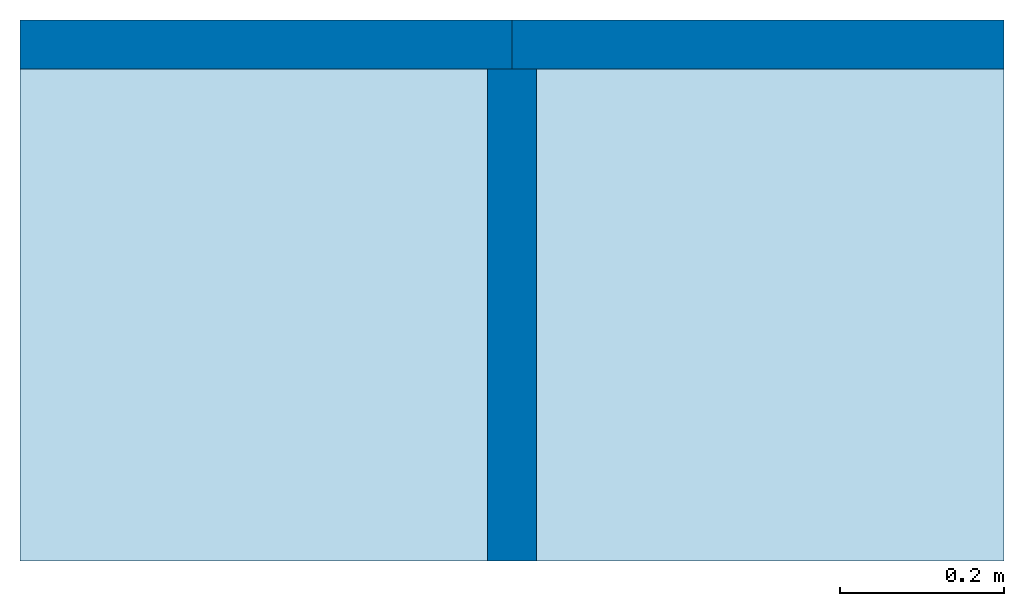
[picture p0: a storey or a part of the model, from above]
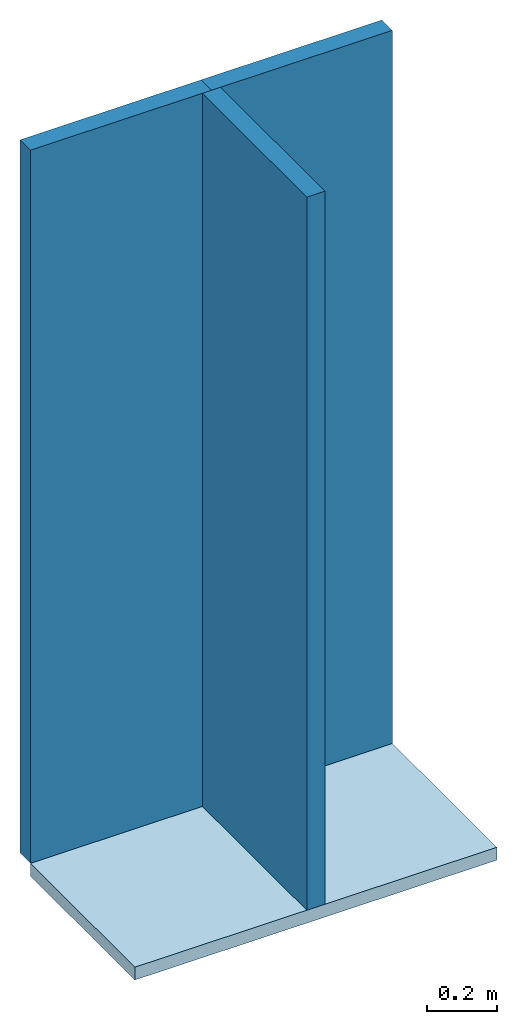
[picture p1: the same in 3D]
Properties of the parts of a building model (IFC2X3)

# File
Description: ViewDefinition [CoordinationView]
Time: 2023-01-18T13:22:00
Written by: The EXPRESS Data Manager Version 5.02.0100.07 : 28 Aug 2013
Made in: 21.1.70.21 - Exporter 21.1.70.21 - Alternate UI 21.1.70.21
Comment: STEP Physical File produced by: The EXPRESS Data Manager Version 5.02.0100.07 : 28 Aug 2013 * Module: EDMstepFileFactory/EDMstandAlone * Creation date: Wed Jan 18 13:22:00 2023 * Host: BIM-LT03 * Database: C:\Users\DONNEE~1\AppData\Local\Temp\6dfd9f73-01cb-4fe2-bb7c-203e315a706e\a5f62d73-1708-4fc1-9576-1699a38a04a9\ifc * Database version: 5507 * Database creation date: Wed Jan 18 13:22:00 2023 * Schema: IFC2X3 * Model: DataRepository.ifc * Model creation date: Wed Jan 18 13:22:00 2023 * Header model: DataRepository.ifc_HeaderModel * Header model creation date: Wed Jan 18 13:22:00 2023 * EDMuser: sdai-user * EDMgroup: sdai-group * License ID and type: 5605 : Permanent license. Expiry date: * EDMstepFileFactory options: 020000

# IfcSite, Default
RefLatitude: 42, 24, 53, 508911; RefLongitude: -71, -15, -29, -58837; RefElevation: 0 mm
Pset_ProductRequirements - Category: Project Information

# IfcBuilding
Pset_BuildingCommon - NumberOfStoreys: 1
Pset_ProductRequirements - Category: Project Information

# IfcBuildingStorey: Level:NL_00_niveau, Begane grond
LongName: Begane grond; Elevation: 0 mm
Pset_AirSideSystemInformation - Name: Begane grond
Pset_ProductRequirements - Name: Begane grond; Category: Levels

# IfcSlab: Floor:NLRS_23_FL_Ultracoustic_60x600x12000mm, Floor:NLRS_23_FL_Ultracoustic_60x600x12000mm:2487
In: Begane grond
Type - PredefinedType: FLOOR; Material: Knauf Insulation_Ecose® glaswol Ultracoustic 45 mm
Type - Pset_ElementShading - Roughness: 304.8 mm
Type - Pset_ManufacturerTypeInformation - Manufacturer: Knauf Insulation B.V.
Type - Pset_ProductRequirements - Category: Floors
Type - Pset_QuantityTakeOff - Reference: Floor:NLRS_23_FL_Ultracoustic_60x600x12000mm
Type - Pset_ReinforcementBarPitchOfSlab - Description: Ultracoustic - 60mm; Reference: Floor:NLRS_23_FL_Ultracoustic_60x600x12000mm
Type - Pset_SlabCommon - IsExternal: no; Reference: Floor:NLRS_23_FL_Ultracoustic_60x600x12000mm; ThermalTransmittance: 0.822222 kg/K/s3
Type - Pset_Floor Schedule Ultracoustic LOD200 - Assembly Code: 23; Type Image: Raster image: Ultracoustic.jpg (2); Model: Ultracoustic is een veerkrachtige onbeklede glaswoldeken met ECOSE® Technology; Manufacturer: Knauf Insulation B.V.; URL: www.knaufinsulation.nl; Description: Ultracoustic - 60mm
Classification: 23 Vloeren (Uniformat)
Pset_SlabCommon - LoadBearing: no; PitchAngle: 0 deg
Pset_Floor Schedule Ultracoustic LOD200 - Type: Floor: NLRS_23_FL_Ultracoustic_60x600x12000mm

# IfcWallStandardCase: Basic Wall:NLRS_22_WA_Ultracoustic_60x600x12000mm (3)
In: Begane grond
Type - PredefinedType: STANDARD; Material: Knauf Insulation_Ecose® glaswol Ultracoustic 60 mm
Type - Pset_ElementShading - Roughness: 304.8 mm
Type - Pset_ManufacturerTypeInformation - Manufacturer: Knauf Insulation B.V.
Type - Pset_ProductRequirements - Category: Walls
Type - Pset_QuantityTakeOff - Reference: Basic Wall:NLRS_22_WA_Ultracoustic_60x600x12000mm
Type - Pset_ReinforcementBarPitchOfWall - Description: Ultracoustic - 60mm; Reference: Basic Wall:NLRS_22_WA_Ultracoustic_60x600x12000mm
Type - Pset_WallCommon - Reference: Basic Wall:NLRS_22_WA_Ultracoustic_60x600x12000mm; ThermalTransmittance: 0.616667 kg/K/s3; IsExternal: no
Type - Pset_Wall Schedule Ultracoustic LOD200 - Assembly Code: 22; Type Image: Raster image: Ultracoustic.jpg (2); Model: Ultracoustic is een veerkrachtige onbeklede glaswoldeken met ECOSE® Technology; Manufacturer: Knauf Insulation B.V.; URL: www.knaufinsulation.nl; Description: Ultracoustic - 60mm
Classification: 22 Binnenwanden (Uniformat)
Pset_WallCommon - ExtendToStructure: no; LoadBearing: no
Pset_Wall Schedule Ultracoustic LOD200 - Type: Basic Wall: NLRS_22_WA_Ultracoustic_60x600x12000mm
Name (Basic Wall:NLRS_22_WA_Ultracoustic_60x600x12000mm:...)
2451
2452
2453
